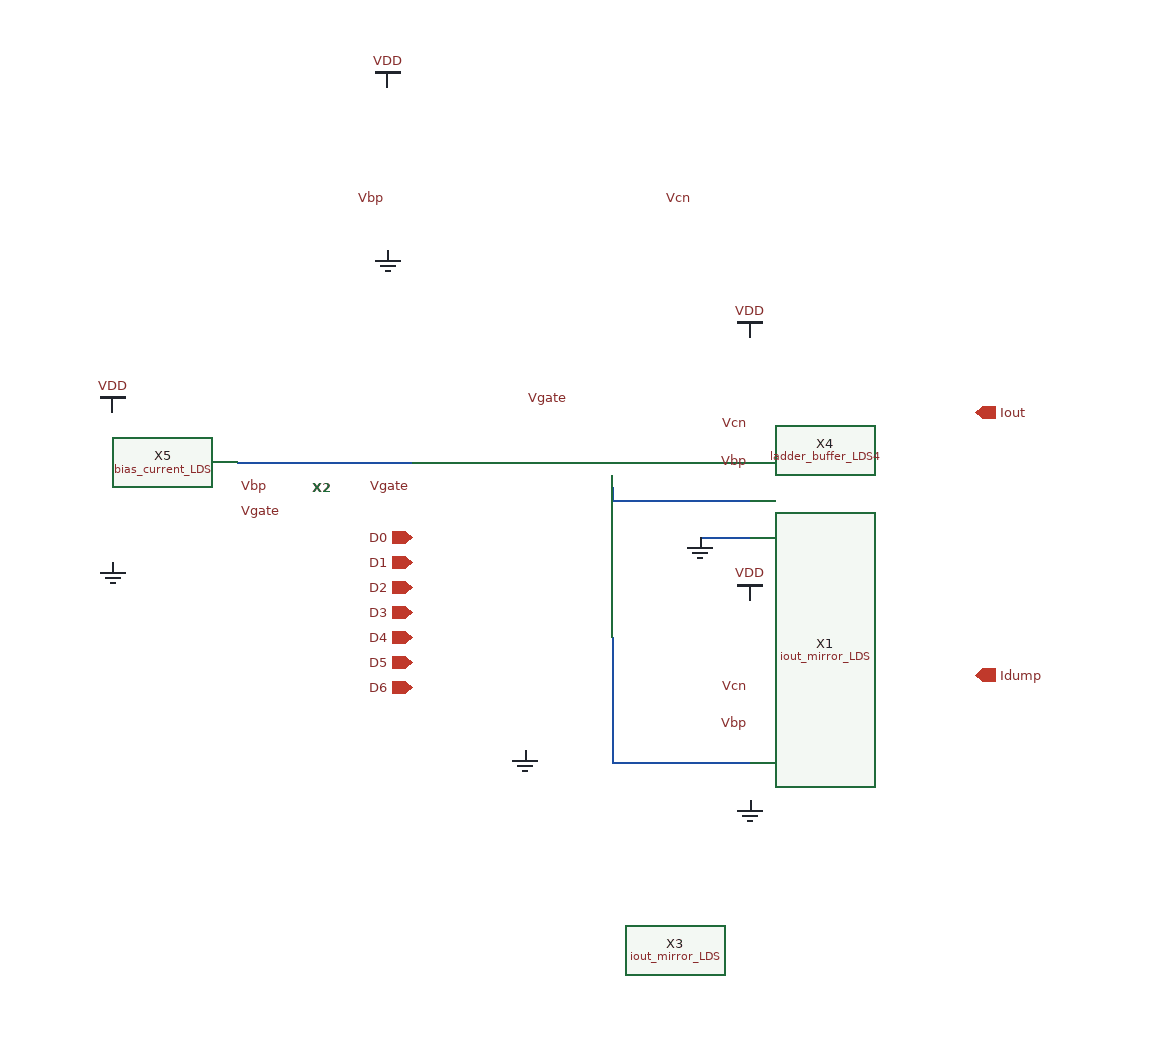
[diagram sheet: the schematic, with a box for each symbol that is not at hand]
v {xschem version=2.9.9 file_version=1.2 }
G {}
K {}
V {}
S {}
E {}
N 1090 -440 1230 -440 { lab=#net1}
N 1460 -380 1500 -380 { lab=GND}
N 1390 -300 1390 -200 { lab=#net2}
N 1390 -200 1500 -200 { lab=#net2}
N 1390 -420 1390 -410 { lab=#net3}
N 1390 -410 1500 -410 { lab=#net3}
C {/home/madvlsi/Desktop/madvlsi/madvlsi_proj_4/schematic/cascode_generator_LDS.sym} 1150 -420 0 0 {name=X2}
C {/home/madvlsi/Desktop/madvlsi/madvlsi_proj_4/schematic/iout_mirror_LDS.sym} 1440 -260 0 0 {name=X1}
C {/home/madvlsi/Desktop/madvlsi/madvlsi_proj_4/schematic/iout_mirror_LDS.sym} 1440 -50 0 0 {name=X3}
C {/home/madvlsi/Desktop/madvlsi/madvlsi_proj_4/schematic/ladder_buffer_LDS4.sym} 1380 -320 0 0 {name=X4}
C {/home/madvlsi/Desktop/madvlsi/madvlsi_proj_4/schematic/bias_current_LDS.sym} 1080 -310 0 0 {name=X5}
C {devices/lab_pin.sym} 1090 -420 2 0 {name=l1 sig_type=std_logic lab=Vbp}
C {devices/lab_pin.sym} 1210 -650 0 0 {name=l2 sig_type=std_logic lab=Vbp}
C {madvlsi/vdd.sym} 1210 -740 0 0 {name=l3 lab=VDD}
C {madvlsi/vdd.sym} 990 -480 0 0 {name=l4 lab=VDD}
C {madvlsi/vdd.sym} 1500 -540 0 0 {name=l5 lab=VDD}
C {madvlsi/vdd.sym} 1500 -330 0 0 {name=l6 lab=VDD}
C {devices/lab_pin.sym} 1090 -400 2 0 {name=l7 sig_type=std_logic lab=Vgate}
C {devices/lab_pin.sym} 1320 -490 2 0 {name=l8 sig_type=std_logic lab=Vgate}
C {devices/lab_pin.sym} 1230 -420 0 0 {name=l9 sig_type=std_logic lab=Vgate}
C {madvlsi/gnd.sym} 1210 -610 0 0 {name=l10 lab=GND}
C {madvlsi/gnd.sym} 990 -360 0 0 {name=l11 lab=GND}
C {madvlsi/gnd.sym} 1320 -210 0 0 {name=l12 lab=GND}
C {madvlsi/gnd.sym} 1500 -170 0 0 {name=l13 lab=GND}
C {madvlsi/gnd.sym} 1460 -380 0 0 {name=l14 lab=GND}
C {devices/lab_pin.sym} 1500 -440 0 0 {name=l15 sig_type=std_logic lab=Vbp}
C {devices/lab_pin.sym} 1500 -230 0 0 {name=l16 sig_type=std_logic lab=Vbp}
C {devices/lab_pin.sym} 1430 -650 2 0 {name=l17 sig_type=std_logic lab=Vcn}
C {devices/lab_pin.sym} 1500 -470 0 0 {name=l18 sig_type=std_logic lab=Vcn}
C {devices/lab_pin.sym} 1500 -260 0 0 {name=l19 sig_type=std_logic lab=Vcn}
C {devices/opin.sym} 1680 -480 0 0 {name=p1 lab=Iout}
C {devices/opin.sym} 1680 -270 0 0 {name=p2 lab=Idump}
C {devices/ipin.sym} 1230 -380 0 0 {name=p3 lab=D0}
C {devices/ipin.sym} 1230 -360 0 0 {name=p4 lab=D1}
C {devices/ipin.sym} 1230 -340 0 0 {name=p5 lab=D2}
C {devices/ipin.sym} 1230 -320 0 0 {name=p6 lab=D3}
C {devices/ipin.sym} 1230 -300 0 0 {name=p7 lab=D4}
C {devices/ipin.sym} 1230 -280 0 0 {name=p8 lab=D5}
C {devices/ipin.sym} 1230 -260 0 0 {name=p9 lab=D6}
